# Generated by FakeRAM 2.0
VERSION 5.7 ;
BUSBITCHARS "[]" ;
PROPERTYDEFINITIONS
  MACRO width INTEGER ;
  MACRO depth INTEGER ;
  MACRO banks INTEGER ;
END PROPERTYDEFINITIONS
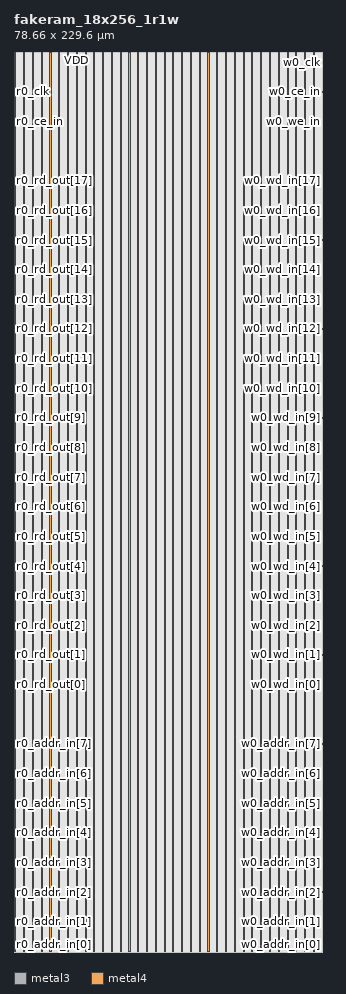
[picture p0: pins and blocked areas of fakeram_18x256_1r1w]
MACRO fakeram_18x256_1r1w
  PROPERTY width 18 ;
  PROPERTY depth 256 ;
  PROPERTY banks 1 ;
  FOREIGN fakeram_18x256_1r1w 0 0 ;
  SYMMETRY X Y R90 ;
  SIZE 78.660 BY 229.600 ;
  CLASS BLOCK ;
  PIN r0_addr_in[0]
    DIRECTION INPUT ;
    USE SIGNAL ;
    SHAPE ABUTMENT ;
    PORT
      LAYER metal3 ;
      RECT 0.000 0.140 0.070 0.210 ;
    END
  END r0_addr_in[0]
  PIN r0_addr_in[1]
    DIRECTION INPUT ;
    USE SIGNAL ;
    SHAPE ABUTMENT ;
    PORT
      LAYER metal3 ;
      RECT 0.000 7.700 0.070 7.770 ;
    END
  END r0_addr_in[1]
  PIN r0_addr_in[2]
    DIRECTION INPUT ;
    USE SIGNAL ;
    SHAPE ABUTMENT ;
    PORT
      LAYER metal3 ;
      RECT 0.000 15.260 0.070 15.330 ;
    END
  END r0_addr_in[2]
  PIN r0_addr_in[3]
    DIRECTION INPUT ;
    USE SIGNAL ;
    SHAPE ABUTMENT ;
    PORT
      LAYER metal3 ;
      RECT 0.000 22.820 0.070 22.890 ;
    END
  END r0_addr_in[3]
  PIN r0_addr_in[4]
    DIRECTION INPUT ;
    USE SIGNAL ;
    SHAPE ABUTMENT ;
    PORT
      LAYER metal3 ;
      RECT 0.000 30.380 0.070 30.450 ;
    END
  END r0_addr_in[4]
  PIN r0_addr_in[5]
    DIRECTION INPUT ;
    USE SIGNAL ;
    SHAPE ABUTMENT ;
    PORT
      LAYER metal3 ;
      RECT 0.000 37.940 0.070 38.010 ;
    END
  END r0_addr_in[5]
  PIN r0_addr_in[6]
    DIRECTION INPUT ;
    USE SIGNAL ;
    SHAPE ABUTMENT ;
    PORT
      LAYER metal3 ;
      RECT 0.000 45.500 0.070 45.570 ;
    END
  END r0_addr_in[6]
  PIN r0_addr_in[7]
    DIRECTION INPUT ;
    USE SIGNAL ;
    SHAPE ABUTMENT ;
    PORT
      LAYER metal3 ;
      RECT 0.000 53.060 0.070 53.130 ;
    END
  END r0_addr_in[7]
  PIN r0_rd_out[0]
    DIRECTION OUTPUT ;
    USE SIGNAL ;
    SHAPE ABUTMENT ;
    PORT
      LAYER metal3 ;
      RECT 0.000 68.180 0.070 68.250 ;
    END
  END r0_rd_out[0]
  PIN r0_rd_out[1]
    DIRECTION OUTPUT ;
    USE SIGNAL ;
    SHAPE ABUTMENT ;
    PORT
      LAYER metal3 ;
      RECT 0.000 75.740 0.070 75.810 ;
    END
  END r0_rd_out[1]
  PIN r0_rd_out[2]
    DIRECTION OUTPUT ;
    USE SIGNAL ;
    SHAPE ABUTMENT ;
    PORT
      LAYER metal3 ;
      RECT 0.000 83.300 0.070 83.370 ;
    END
  END r0_rd_out[2]
  PIN r0_rd_out[3]
    DIRECTION OUTPUT ;
    USE SIGNAL ;
    SHAPE ABUTMENT ;
    PORT
      LAYER metal3 ;
      RECT 0.000 90.860 0.070 90.930 ;
    END
  END r0_rd_out[3]
  PIN r0_rd_out[4]
    DIRECTION OUTPUT ;
    USE SIGNAL ;
    SHAPE ABUTMENT ;
    PORT
      LAYER metal3 ;
      RECT 0.000 98.420 0.070 98.490 ;
    END
  END r0_rd_out[4]
  PIN r0_rd_out[5]
    DIRECTION OUTPUT ;
    USE SIGNAL ;
    SHAPE ABUTMENT ;
    PORT
      LAYER metal3 ;
      RECT 0.000 105.980 0.070 106.050 ;
    END
  END r0_rd_out[5]
  PIN r0_rd_out[6]
    DIRECTION OUTPUT ;
    USE SIGNAL ;
    SHAPE ABUTMENT ;
    PORT
      LAYER metal3 ;
      RECT 0.000 113.540 0.070 113.610 ;
    END
  END r0_rd_out[6]
  PIN r0_rd_out[7]
    DIRECTION OUTPUT ;
    USE SIGNAL ;
    SHAPE ABUTMENT ;
    PORT
      LAYER metal3 ;
      RECT 0.000 121.100 0.070 121.170 ;
    END
  END r0_rd_out[7]
  PIN r0_rd_out[8]
    DIRECTION OUTPUT ;
    USE SIGNAL ;
    SHAPE ABUTMENT ;
    PORT
      LAYER metal3 ;
      RECT 0.000 128.660 0.070 128.730 ;
    END
  END r0_rd_out[8]
  PIN r0_rd_out[9]
    DIRECTION OUTPUT ;
    USE SIGNAL ;
    SHAPE ABUTMENT ;
    PORT
      LAYER metal3 ;
      RECT 0.000 136.220 0.070 136.290 ;
    END
  END r0_rd_out[9]
  PIN r0_rd_out[10]
    DIRECTION OUTPUT ;
    USE SIGNAL ;
    SHAPE ABUTMENT ;
    PORT
      LAYER metal3 ;
      RECT 0.000 143.780 0.070 143.850 ;
    END
  END r0_rd_out[10]
  PIN r0_rd_out[11]
    DIRECTION OUTPUT ;
    USE SIGNAL ;
    SHAPE ABUTMENT ;
    PORT
      LAYER metal3 ;
      RECT 0.000 151.340 0.070 151.410 ;
    END
  END r0_rd_out[11]
  PIN r0_rd_out[12]
    DIRECTION OUTPUT ;
    USE SIGNAL ;
    SHAPE ABUTMENT ;
    PORT
      LAYER metal3 ;
      RECT 0.000 158.900 0.070 158.970 ;
    END
  END r0_rd_out[12]
  PIN r0_rd_out[13]
    DIRECTION OUTPUT ;
    USE SIGNAL ;
    SHAPE ABUTMENT ;
    PORT
      LAYER metal3 ;
      RECT 0.000 166.460 0.070 166.530 ;
    END
  END r0_rd_out[13]
  PIN r0_rd_out[14]
    DIRECTION OUTPUT ;
    USE SIGNAL ;
    SHAPE ABUTMENT ;
    PORT
      LAYER metal3 ;
      RECT 0.000 174.020 0.070 174.090 ;
    END
  END r0_rd_out[14]
  PIN r0_rd_out[15]
    DIRECTION OUTPUT ;
    USE SIGNAL ;
    SHAPE ABUTMENT ;
    PORT
      LAYER metal3 ;
      RECT 0.000 181.580 0.070 181.650 ;
    END
  END r0_rd_out[15]
  PIN r0_rd_out[16]
    DIRECTION OUTPUT ;
    USE SIGNAL ;
    SHAPE ABUTMENT ;
    PORT
      LAYER metal3 ;
      RECT 0.000 189.140 0.070 189.210 ;
    END
  END r0_rd_out[16]
  PIN r0_rd_out[17]
    DIRECTION OUTPUT ;
    USE SIGNAL ;
    SHAPE ABUTMENT ;
    PORT
      LAYER metal3 ;
      RECT 0.000 196.700 0.070 196.770 ;
    END
  END r0_rd_out[17]
  PIN r0_ce_in
    DIRECTION INPUT ;
    USE SIGNAL ;
    SHAPE ABUTMENT ;
    PORT
      LAYER metal3 ;
      RECT 0.000 211.820 0.070 211.890 ;
    END
  END r0_ce_in
  PIN r0_clk
    DIRECTION INPUT ;
    USE SIGNAL ;
    SHAPE ABUTMENT ;
    PORT
      LAYER metal3 ;
      RECT 0.000 219.380 0.070 219.450 ;
    END
  END r0_clk
  PIN w0_addr_in[0]
    DIRECTION INPUT ;
    USE SIGNAL ;
    SHAPE ABUTMENT ;
    PORT
      LAYER metal3 ;
      RECT 78.590 0.140 78.660 0.210 ;
    END
  END w0_addr_in[0]
  PIN w0_addr_in[1]
    DIRECTION INPUT ;
    USE SIGNAL ;
    SHAPE ABUTMENT ;
    PORT
      LAYER metal3 ;
      RECT 78.590 7.700 78.660 7.770 ;
    END
  END w0_addr_in[1]
  PIN w0_addr_in[2]
    DIRECTION INPUT ;
    USE SIGNAL ;
    SHAPE ABUTMENT ;
    PORT
      LAYER metal3 ;
      RECT 78.590 15.260 78.660 15.330 ;
    END
  END w0_addr_in[2]
  PIN w0_addr_in[3]
    DIRECTION INPUT ;
    USE SIGNAL ;
    SHAPE ABUTMENT ;
    PORT
      LAYER metal3 ;
      RECT 78.590 22.820 78.660 22.890 ;
    END
  END w0_addr_in[3]
  PIN w0_addr_in[4]
    DIRECTION INPUT ;
    USE SIGNAL ;
    SHAPE ABUTMENT ;
    PORT
      LAYER metal3 ;
      RECT 78.590 30.380 78.660 30.450 ;
    END
  END w0_addr_in[4]
  PIN w0_addr_in[5]
    DIRECTION INPUT ;
    USE SIGNAL ;
    SHAPE ABUTMENT ;
    PORT
      LAYER metal3 ;
      RECT 78.590 37.940 78.660 38.010 ;
    END
  END w0_addr_in[5]
  PIN w0_addr_in[6]
    DIRECTION INPUT ;
    USE SIGNAL ;
    SHAPE ABUTMENT ;
    PORT
      LAYER metal3 ;
      RECT 78.590 45.500 78.660 45.570 ;
    END
  END w0_addr_in[6]
  PIN w0_addr_in[7]
    DIRECTION INPUT ;
    USE SIGNAL ;
    SHAPE ABUTMENT ;
    PORT
      LAYER metal3 ;
      RECT 78.590 53.060 78.660 53.130 ;
    END
  END w0_addr_in[7]
  PIN w0_wd_in[0]
    DIRECTION INPUT ;
    USE SIGNAL ;
    SHAPE ABUTMENT ;
    PORT
      LAYER metal3 ;
      RECT 78.590 68.180 78.660 68.250 ;
    END
  END w0_wd_in[0]
  PIN w0_wd_in[1]
    DIRECTION INPUT ;
    USE SIGNAL ;
    SHAPE ABUTMENT ;
    PORT
      LAYER metal3 ;
      RECT 78.590 75.740 78.660 75.810 ;
    END
  END w0_wd_in[1]
  PIN w0_wd_in[2]
    DIRECTION INPUT ;
    USE SIGNAL ;
    SHAPE ABUTMENT ;
    PORT
      LAYER metal3 ;
      RECT 78.590 83.300 78.660 83.370 ;
    END
  END w0_wd_in[2]
  PIN w0_wd_in[3]
    DIRECTION INPUT ;
    USE SIGNAL ;
    SHAPE ABUTMENT ;
    PORT
      LAYER metal3 ;
      RECT 78.590 90.860 78.660 90.930 ;
    END
  END w0_wd_in[3]
  PIN w0_wd_in[4]
    DIRECTION INPUT ;
    USE SIGNAL ;
    SHAPE ABUTMENT ;
    PORT
      LAYER metal3 ;
      RECT 78.590 98.420 78.660 98.490 ;
    END
  END w0_wd_in[4]
  PIN w0_wd_in[5]
    DIRECTION INPUT ;
    USE SIGNAL ;
    SHAPE ABUTMENT ;
    PORT
      LAYER metal3 ;
      RECT 78.590 105.980 78.660 106.050 ;
    END
  END w0_wd_in[5]
  PIN w0_wd_in[6]
    DIRECTION INPUT ;
    USE SIGNAL ;
    SHAPE ABUTMENT ;
    PORT
      LAYER metal3 ;
      RECT 78.590 113.540 78.660 113.610 ;
    END
  END w0_wd_in[6]
  PIN w0_wd_in[7]
    DIRECTION INPUT ;
    USE SIGNAL ;
    SHAPE ABUTMENT ;
    PORT
      LAYER metal3 ;
      RECT 78.590 121.100 78.660 121.170 ;
    END
  END w0_wd_in[7]
  PIN w0_wd_in[8]
    DIRECTION INPUT ;
    USE SIGNAL ;
    SHAPE ABUTMENT ;
    PORT
      LAYER metal3 ;
      RECT 78.590 128.660 78.660 128.730 ;
    END
  END w0_wd_in[8]
  PIN w0_wd_in[9]
    DIRECTION INPUT ;
    USE SIGNAL ;
    SHAPE ABUTMENT ;
    PORT
      LAYER metal3 ;
      RECT 78.590 136.220 78.660 136.290 ;
    END
  END w0_wd_in[9]
  PIN w0_wd_in[10]
    DIRECTION INPUT ;
    USE SIGNAL ;
    SHAPE ABUTMENT ;
    PORT
      LAYER metal3 ;
      RECT 78.590 143.780 78.660 143.850 ;
    END
  END w0_wd_in[10]
  PIN w0_wd_in[11]
    DIRECTION INPUT ;
    USE SIGNAL ;
    SHAPE ABUTMENT ;
    PORT
      LAYER metal3 ;
      RECT 78.590 151.340 78.660 151.410 ;
    END
  END w0_wd_in[11]
  PIN w0_wd_in[12]
    DIRECTION INPUT ;
    USE SIGNAL ;
    SHAPE ABUTMENT ;
    PORT
      LAYER metal3 ;
      RECT 78.590 158.900 78.660 158.970 ;
    END
  END w0_wd_in[12]
  PIN w0_wd_in[13]
    DIRECTION INPUT ;
    USE SIGNAL ;
    SHAPE ABUTMENT ;
    PORT
      LAYER metal3 ;
      RECT 78.590 166.460 78.660 166.530 ;
    END
  END w0_wd_in[13]
  PIN w0_wd_in[14]
    DIRECTION INPUT ;
    USE SIGNAL ;
    SHAPE ABUTMENT ;
    PORT
      LAYER metal3 ;
      RECT 78.590 174.020 78.660 174.090 ;
    END
  END w0_wd_in[14]
  PIN w0_wd_in[15]
    DIRECTION INPUT ;
    USE SIGNAL ;
    SHAPE ABUTMENT ;
    PORT
      LAYER metal3 ;
      RECT 78.590 181.580 78.660 181.650 ;
    END
  END w0_wd_in[15]
  PIN w0_wd_in[16]
    DIRECTION INPUT ;
    USE SIGNAL ;
    SHAPE ABUTMENT ;
    PORT
      LAYER metal3 ;
      RECT 78.590 189.140 78.660 189.210 ;
    END
  END w0_wd_in[16]
  PIN w0_wd_in[17]
    DIRECTION INPUT ;
    USE SIGNAL ;
    SHAPE ABUTMENT ;
    PORT
      LAYER metal3 ;
      RECT 78.590 196.700 78.660 196.770 ;
    END
  END w0_wd_in[17]
  PIN w0_we_in
    DIRECTION INPUT ;
    USE SIGNAL ;
    SHAPE ABUTMENT ;
    PORT
      LAYER metal3 ;
      RECT 78.590 211.820 78.660 211.890 ;
    END
  END w0_we_in
  PIN w0_ce_in
    DIRECTION INPUT ;
    USE SIGNAL ;
    SHAPE ABUTMENT ;
    PORT
      LAYER metal3 ;
      RECT 78.590 219.380 78.660 219.450 ;
    END
  END w0_ce_in
  PIN w0_clk
    DIRECTION INPUT ;
    USE SIGNAL ;
    SHAPE ABUTMENT ;
    PORT
      LAYER metal3 ;
      RECT 78.590 226.940 78.660 227.010 ;
    END
  END w0_clk
  PIN VSS
    DIRECTION INOUT ;
    USE GROUND ;
    PORT
      LAYER metal4 ;
      RECT 0.210 0.140 0.490 229.460 ;
      RECT 2.450 0.140 2.730 229.460 ;
      RECT 4.690 0.140 4.970 229.460 ;
      RECT 6.930 0.140 7.210 229.460 ;
      RECT 9.170 0.140 9.450 229.460 ;
      RECT 11.410 0.140 11.690 229.460 ;
      RECT 13.650 0.140 13.930 229.460 ;
      RECT 15.890 0.140 16.170 229.460 ;
      RECT 18.130 0.140 18.410 229.460 ;
      RECT 20.370 0.140 20.650 229.460 ;
      RECT 22.610 0.140 22.890 229.460 ;
      RECT 24.850 0.140 25.130 229.460 ;
      RECT 27.090 0.140 27.370 229.460 ;
      RECT 29.330 0.140 29.610 229.460 ;
      RECT 31.570 0.140 31.850 229.460 ;
      RECT 33.810 0.140 34.090 229.460 ;
      RECT 36.050 0.140 36.330 229.460 ;
      RECT 38.290 0.140 38.570 229.460 ;
      RECT 40.530 0.140 40.810 229.460 ;
      RECT 42.770 0.140 43.050 229.460 ;
      RECT 45.010 0.140 45.290 229.460 ;
      RECT 47.250 0.140 47.530 229.460 ;
      RECT 49.490 0.140 49.770 229.460 ;
      RECT 51.730 0.140 52.010 229.460 ;
      RECT 53.970 0.140 54.250 229.460 ;
      RECT 56.210 0.140 56.490 229.460 ;
      RECT 58.450 0.140 58.730 229.460 ;
      RECT 60.690 0.140 60.970 229.460 ;
      RECT 62.930 0.140 63.210 229.460 ;
      RECT 65.170 0.140 65.450 229.460 ;
      RECT 67.410 0.140 67.690 229.460 ;
      RECT 69.650 0.140 69.930 229.460 ;
      RECT 71.890 0.140 72.170 229.460 ;
      RECT 74.130 0.140 74.410 229.460 ;
      RECT 76.370 0.140 76.650 229.460 ;
    END
  END VSS
  PIN VDD
    DIRECTION INOUT ;
    USE POWER ;
    PORT
      LAYER metal4 ;
      RECT 0.210 0.140 0.490 229.460 ;
      RECT 2.450 0.140 2.730 229.460 ;
      RECT 4.690 0.140 4.970 229.460 ;
      RECT 6.930 0.140 7.210 229.460 ;
      RECT 9.170 0.140 9.450 229.460 ;
      RECT 11.410 0.140 11.690 229.460 ;
      RECT 13.650 0.140 13.930 229.460 ;
      RECT 15.890 0.140 16.170 229.460 ;
      RECT 18.130 0.140 18.410 229.460 ;
      RECT 20.370 0.140 20.650 229.460 ;
      RECT 22.610 0.140 22.890 229.460 ;
      RECT 24.850 0.140 25.130 229.460 ;
      RECT 27.090 0.140 27.370 229.460 ;
      RECT 29.330 0.140 29.610 229.460 ;
      RECT 31.570 0.140 31.850 229.460 ;
      RECT 33.810 0.140 34.090 229.460 ;
      RECT 36.050 0.140 36.330 229.460 ;
      RECT 38.290 0.140 38.570 229.460 ;
      RECT 40.530 0.140 40.810 229.460 ;
      RECT 42.770 0.140 43.050 229.460 ;
      RECT 45.010 0.140 45.290 229.460 ;
      RECT 47.250 0.140 47.530 229.460 ;
      RECT 49.490 0.140 49.770 229.460 ;
      RECT 51.730 0.140 52.010 229.460 ;
      RECT 53.970 0.140 54.250 229.460 ;
      RECT 56.210 0.140 56.490 229.460 ;
      RECT 58.450 0.140 58.730 229.460 ;
      RECT 60.690 0.140 60.970 229.460 ;
      RECT 62.930 0.140 63.210 229.460 ;
      RECT 65.170 0.140 65.450 229.460 ;
      RECT 67.410 0.140 67.690 229.460 ;
      RECT 69.650 0.140 69.930 229.460 ;
      RECT 71.890 0.140 72.170 229.460 ;
      RECT 74.130 0.140 74.410 229.460 ;
      RECT 76.370 0.140 76.650 229.460 ;
    END
  END VDD
  OBS
    LAYER metal1 ;
    RECT 0 0 78.660 229.600 ;
    LAYER metal2 ;
    RECT 0 0 78.660 229.600 ;
    LAYER metal3 ;
    RECT 0 0 78.660 229.600 ;
    LAYER metal4 ;
    RECT 0 0 78.660 229.600 ;
    LAYER OVERLAP ;
    RECT 0 0 78.660 229.600 ;
  END
END fakeram_18x256_1r1w

END LIBRARY
